VERSION 5.7 ;
  NOWIREEXTENSIONATPIN ON ;
  DIVIDERCHAR "/" ;
  BUSBITCHARS "[]" ;
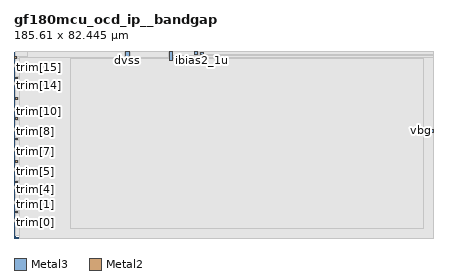
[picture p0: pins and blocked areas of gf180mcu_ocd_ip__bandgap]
MACRO gf180mcu_ocd_ip__bandgap
  CLASS BLOCK ;
  FOREIGN gf180mcu_ocd_ip__bandgap ;
  ORIGIN 44.050 152.485 ;
  SIZE 185.610 BY 82.445 ;
  PIN dvdd
    ANTENNAGATEAREA 87.000000 ;
    ANTENNADIFFAREA 429.752502 ;
    PORT
      LAYER Metal3 ;
        RECT 35.830 -71.610 37.020 -70.220 ;
    END
  END dvdd
  PIN vbg
    ANTENNAGATEAREA 48.000000 ;
    ANTENNADIFFAREA 14.080000 ;
    PORT
      LAYER Metal3 ;
        RECT 139.230 -105.730 141.385 -104.575 ;
    END
  END vbg
  PIN dvss
    ANTENNAGATEAREA 416.160004 ;
    ANTENNADIFFAREA 764.642700 ;
    PORT
      LAYER Metal3 ;
        RECT 5.110 -74.230 7.155 -70.195 ;
    END
  END dvss
  PIN ibias1_250n
    ANTENNAGATEAREA 40.000000 ;
    ANTENNADIFFAREA 7.381200 ;
    PORT
      LAYER Metal3 ;
        RECT 24.630 -73.860 25.785 -70.040 ;
    END
  END ibias1_250n
  PIN trim[15]
    ANTENNAGATEAREA 0.666400 ;
    ANTENNADIFFAREA 0.438500 ;
    PORT
      LAYER Metal2 ;
        RECT -43.465 -77.605 -42.315 -77.020 ;
    END
  END trim[15]
  PIN trim[14]
    ANTENNAGATEAREA 0.666400 ;
    ANTENNADIFFAREA 0.438500 ;
    PORT
      LAYER Metal2 ;
        RECT -43.465 -82.120 -42.315 -81.515 ;
    END
  END trim[14]
  PIN trim[13]
    ANTENNAGATEAREA 0.666400 ;
    ANTENNADIFFAREA 0.438500 ;
    PORT
      LAYER Metal2 ;
        RECT -43.490 -86.590 -42.335 -85.985 ;
    END
  END trim[13]
  PIN trim[12]
    ANTENNAGATEAREA 0.666400 ;
    ANTENNADIFFAREA 0.438500 ;
    PORT
      LAYER Metal2 ;
        RECT -43.490 -91.080 -42.335 -90.475 ;
    END
  END trim[12]
  PIN trim[11]
    ANTENNAGATEAREA 0.666400 ;
    ANTENNADIFFAREA 0.438500 ;
    PORT
      LAYER Metal2 ;
        RECT -43.490 -95.555 -42.335 -94.950 ;
    END
  END trim[11]
  PIN trim[10]
    ANTENNAGATEAREA 0.666400 ;
    ANTENNADIFFAREA 0.438500 ;
    PORT
      LAYER Metal2 ;
        RECT -43.480 -100.040 -42.325 -99.435 ;
    END
  END trim[10]
  PIN trim[9]
    ANTENNAGATEAREA 0.666400 ;
    ANTENNADIFFAREA 0.438500 ;
    PORT
      LAYER Metal2 ;
        RECT -43.450 -104.500 -42.295 -103.890 ;
    END
  END trim[9]
  PIN trim[8]
    ANTENNAGATEAREA 0.666400 ;
    ANTENNADIFFAREA 0.438500 ;
    PORT
      LAYER Metal2 ;
        RECT -43.460 -109.020 -42.305 -108.415 ;
    END
  END trim[8]
  PIN trim[7]
    ANTENNAGATEAREA 0.666400 ;
    ANTENNADIFFAREA 0.438500 ;
    PORT
      LAYER Metal2 ;
        RECT -43.465 -114.490 -42.315 -113.885 ;
    END
  END trim[7]
  PIN trim[6]
    ANTENNAGATEAREA 0.666400 ;
    ANTENNADIFFAREA 0.438500 ;
    PORT
      LAYER Metal2 ;
        RECT -43.450 -118.955 -42.295 -118.350 ;
    END
  END trim[6]
  PIN trim[5]
    ANTENNAGATEAREA 0.666400 ;
    ANTENNADIFFAREA 0.438500 ;
    PORT
      LAYER Metal2 ;
        RECT -43.480 -123.460 -42.325 -122.855 ;
    END
  END trim[5]
  PIN trim[4]
    ANTENNAGATEAREA 0.666400 ;
    ANTENNADIFFAREA 0.438500 ;
    PORT
      LAYER Metal2 ;
        RECT -43.490 -127.945 -42.335 -127.340 ;
    END
  END trim[4]
  PIN trim[3]
    ANTENNAGATEAREA 0.666400 ;
    ANTENNADIFFAREA 0.438500 ;
    PORT
      LAYER Metal2 ;
        RECT -43.465 -132.410 -42.315 -131.800 ;
    END
  END trim[3]
  PIN trim[2]
    ANTENNAGATEAREA 0.666400 ;
    ANTENNADIFFAREA 0.438500 ;
    PORT
      LAYER Metal2 ;
        RECT -43.440 -136.895 -42.285 -136.290 ;
    END
  END trim[2]
  PIN trim[1]
    ANTENNAGATEAREA 0.666400 ;
    ANTENNADIFFAREA 0.438500 ;
    PORT
      LAYER Metal2 ;
        RECT -43.460 -141.380 -42.305 -140.775 ;
    END
  END trim[1]
  PIN trim[0]
    ANTENNAGATEAREA 0.666400 ;
    ANTENNADIFFAREA 0.438500 ;
    PORT
      LAYER Metal2 ;
        RECT -43.425 -145.840 -42.270 -145.235 ;
    END
  END trim[0]
  PIN ena
    ANTENNAGATEAREA 0.666400 ;
    ANTENNADIFFAREA 0.438500 ;
    PORT
      LAYER Metal2 ;
        RECT -44.050 -73.060 -42.895 -72.470 ;
    END
  END ena
  PIN ibias2_1u
    ANTENNAGATEAREA 6.000000 ;
    ANTENNADIFFAREA 5.531500 ;
    PORT
      LAYER Metal3 ;
        RECT 38.345 -71.270 39.500 -70.320 ;
    END
  END ibias2_1u
  OBS
      LAYER Nwell ;
        RECT -41.685 -150.620 139.680 -70.040 ;
      LAYER Metal1 ;
        RECT -41.555 -150.575 140.400 -70.040 ;
      LAYER Metal2 ;
        RECT -43.490 -72.170 140.310 -70.040 ;
        RECT -42.595 -73.360 140.310 -72.170 ;
        RECT -43.490 -76.720 140.310 -73.360 ;
        RECT -42.015 -77.905 140.310 -76.720 ;
        RECT -43.490 -81.215 140.310 -77.905 ;
        RECT -42.015 -82.420 140.310 -81.215 ;
        RECT -43.490 -85.685 140.310 -82.420 ;
        RECT -42.035 -86.890 140.310 -85.685 ;
        RECT -43.490 -90.175 140.310 -86.890 ;
        RECT -42.035 -91.380 140.310 -90.175 ;
        RECT -43.490 -94.650 140.310 -91.380 ;
        RECT -42.035 -95.855 140.310 -94.650 ;
        RECT -43.490 -99.135 140.310 -95.855 ;
        RECT -42.025 -100.340 140.310 -99.135 ;
        RECT -43.490 -103.590 140.310 -100.340 ;
        RECT -41.995 -104.800 140.310 -103.590 ;
        RECT -43.490 -108.115 140.310 -104.800 ;
        RECT -42.005 -109.320 140.310 -108.115 ;
        RECT -43.490 -113.585 140.310 -109.320 ;
        RECT -42.015 -114.790 140.310 -113.585 ;
        RECT -43.490 -118.050 140.310 -114.790 ;
        RECT -41.995 -119.255 140.310 -118.050 ;
        RECT -43.490 -122.555 140.310 -119.255 ;
        RECT -42.025 -123.760 140.310 -122.555 ;
        RECT -43.490 -127.040 140.310 -123.760 ;
        RECT -42.035 -128.245 140.310 -127.040 ;
        RECT -43.490 -131.500 140.310 -128.245 ;
        RECT -42.015 -132.710 140.310 -131.500 ;
        RECT -43.490 -135.990 140.310 -132.710 ;
        RECT -41.985 -137.195 140.310 -135.990 ;
        RECT -43.490 -140.475 140.310 -137.195 ;
        RECT -42.005 -141.680 140.310 -140.475 ;
        RECT -43.490 -144.935 140.310 -141.680 ;
        RECT -41.970 -146.140 140.310 -144.935 ;
        RECT -43.490 -151.405 140.310 -146.140 ;
      LAYER Metal3 ;
        RECT -38.300 -74.530 4.810 -70.155 ;
        RECT 7.455 -74.160 24.330 -70.155 ;
        RECT 26.085 -71.910 35.530 -70.155 ;
        RECT 37.320 -71.570 38.045 -70.155 ;
        RECT 39.800 -71.570 141.560 -70.155 ;
        RECT 37.320 -71.910 141.560 -71.570 ;
        RECT 26.085 -74.160 141.560 -71.910 ;
        RECT 7.455 -74.530 141.560 -74.160 ;
        RECT -38.300 -104.275 141.560 -74.530 ;
        RECT -38.300 -106.030 138.930 -104.275 ;
        RECT -38.300 -152.485 141.560 -106.030 ;
      LAYER Metal4 ;
        RECT -41.430 -152.485 141.180 -72.680 ;
      LAYER Metal5 ;
        RECT -19.250 -148.330 137.080 -72.965 ;
  END
END gf180mcu_ocd_ip__bandgap
END LIBRARY

